VERSION 5.8 ;
BUSBITCHARS "[]" ;
DIVIDERCHAR "/" ;
UNITS
  DATABASE MICRONS 2000 ;
END UNITS
MANUFACTURINGGRID 0.005 ;

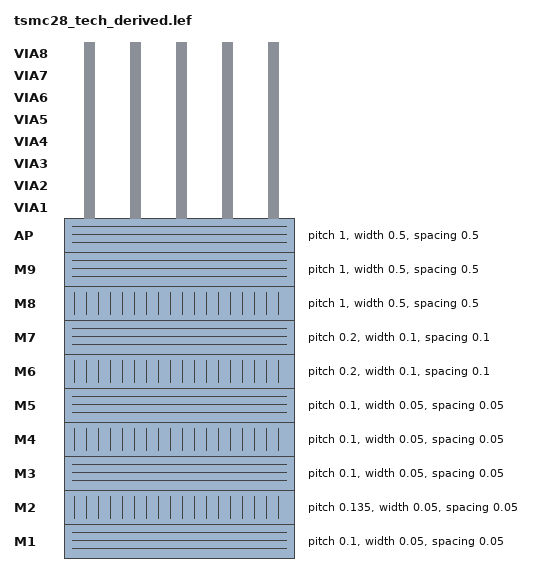
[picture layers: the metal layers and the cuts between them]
LAYER M1
  TYPE ROUTING ;
  DIRECTION HORIZONTAL ;
  PITCH 0.100 ;
  WIDTH 0.050 ;
  SPACING 0.050 ;
END M1

LAYER M2
  TYPE ROUTING ;
  DIRECTION VERTICAL ;
  PITCH 0.135 ;
  WIDTH 0.050 ;
  SPACING 0.050 ;
END M2

LAYER M3
  TYPE ROUTING ;
  DIRECTION HORIZONTAL ;
  PITCH 0.100 ;
  WIDTH 0.050 ;
  SPACING 0.050 ;
END M3

LAYER M4
  TYPE ROUTING ;
  DIRECTION VERTICAL ;
  PITCH 0.100 ;
  WIDTH 0.050 ;
  SPACING 0.050 ;
END M4

LAYER M5
  TYPE ROUTING ;
  DIRECTION HORIZONTAL ;
  PITCH 0.100 ;
  WIDTH 0.050 ;
  SPACING 0.050 ;
END M5

LAYER M6
  TYPE ROUTING ;
  DIRECTION VERTICAL ;
  PITCH 0.200 ;
  WIDTH 0.100 ;
  SPACING 0.100 ;
END M6

LAYER M7
  TYPE ROUTING ;
  DIRECTION HORIZONTAL ;
  PITCH 0.200 ;
  WIDTH 0.100 ;
  SPACING 0.100 ;
END M7

LAYER M8
  TYPE ROUTING ;
  DIRECTION VERTICAL ;
  PITCH 1.000 ;
  WIDTH 0.500 ;
  SPACING 0.5 ;
END M8

LAYER M9
  TYPE ROUTING ;
  DIRECTION HORIZONTAL ;
  PITCH 1.000 ;
  WIDTH 0.500 ;
  SPACING 0.5 ;
END M9

LAYER AP
  TYPE ROUTING ;
  DIRECTION HORIZONTAL ;
  PITCH 1.000 ;
  WIDTH 0.500 ;
  SPACING 0.500 ;
END AP

LAYER VIA1
  TYPE CUT ;
END VIA1

LAYER VIA2
  TYPE CUT ;
END VIA2

LAYER VIA3
  TYPE CUT ;
END VIA3

LAYER VIA4
  TYPE CUT ;
END VIA4

LAYER VIA5
  TYPE CUT ;
END VIA5

LAYER VIA6
  TYPE CUT ;
END VIA6

LAYER VIA7
  TYPE CUT ;
END VIA7

LAYER VIA8
  TYPE CUT ;
END VIA8

SITE core7T
  CLASS CORE ;
  SYMMETRY X Y ;
  SIZE 0.140 BY 0.700 ;
END core7T

END LIBRARY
